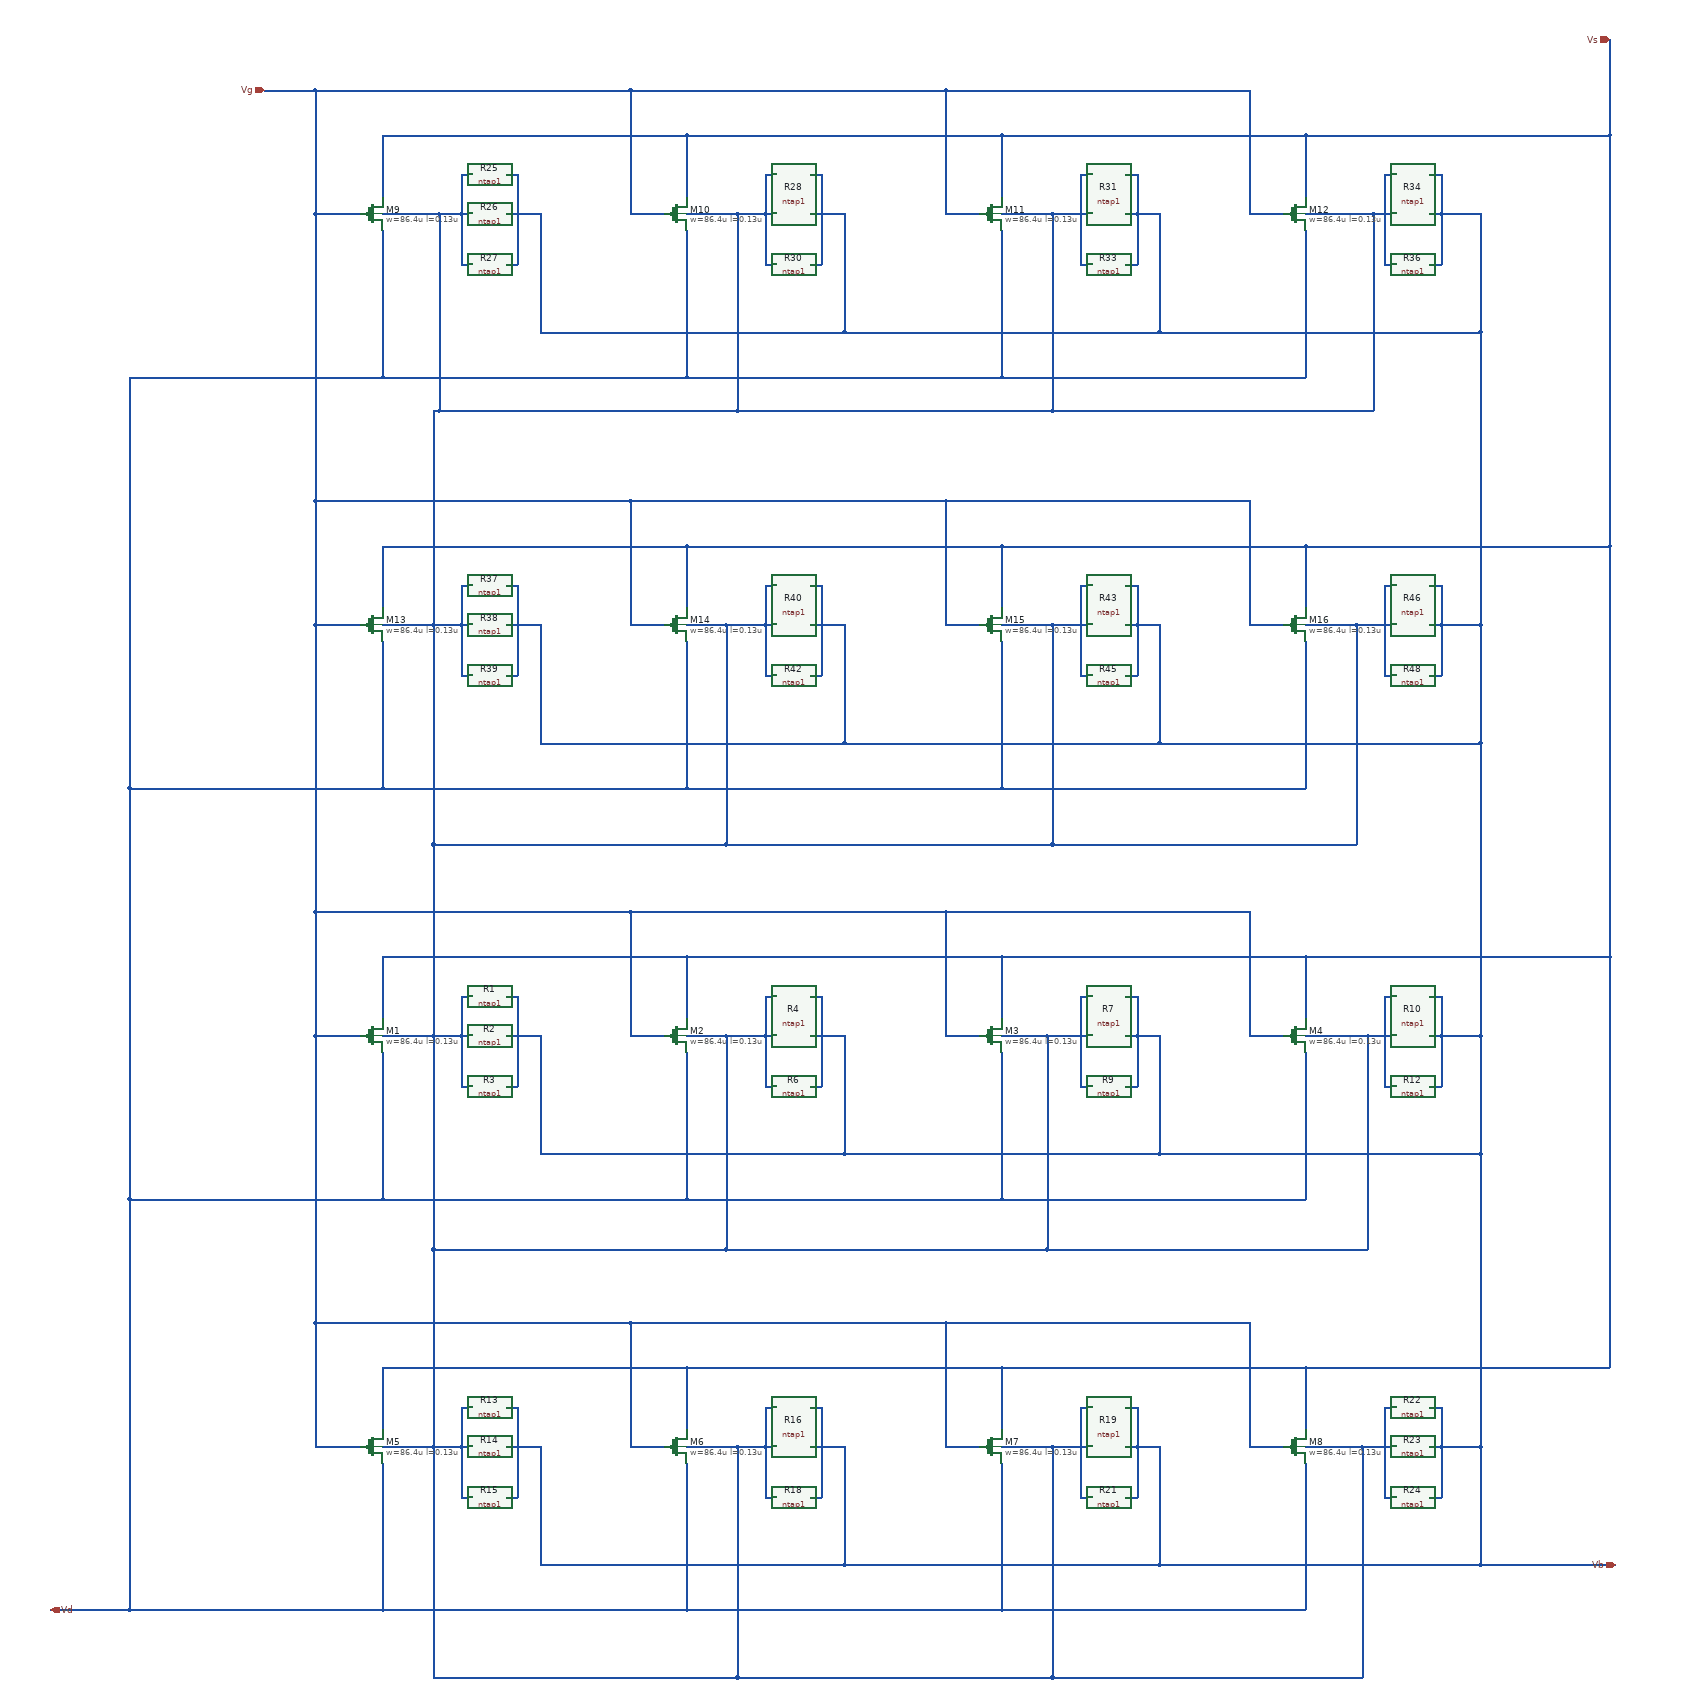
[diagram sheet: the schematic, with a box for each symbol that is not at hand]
v {xschem version=3.4.6 file_version=1.2}
G {}
K {}
V {}
S {}
E {}
N 840 -1420 890 -1420 {lab=#net1}
N 890 -1490 890 -1420 {lab=#net1}
N 890 -1490 910 -1490 {lab=#net1}
N 890 -1420 910 -1420 {lab=#net1}
N 890 -1420 890 -1330 {lab=#net1}
N 890 -1330 910 -1330 {lab=#net1}
N 970 -1490 990 -1490 {lab=Vb}
N 990 -1420 990 -1330 {lab=Vb}
N 970 -1330 990 -1330 {lab=Vb}
N 970 -1420 990 -1420 {lab=Vb}
N 990 -1490 990 -1420 {lab=Vb}
N 750 -1390 750 -1130 {lab=Vd}
N 990 -1420 1030 -1420 {lab=Vb}
N 1360 -1420 1430 -1420 {lab=#net1}
N 1430 -1490 1430 -1420 {lab=#net1}
N 1430 -1490 1450 -1490 {lab=#net1}
N 1430 -1420 1450 -1420 {lab=#net1}
N 1430 -1420 1430 -1330 {lab=#net1}
N 1430 -1330 1450 -1330 {lab=#net1}
N 1510 -1490 1530 -1490 {lab=Vb}
N 1530 -1420 1530 -1330 {lab=Vb}
N 1510 -1330 1530 -1330 {lab=Vb}
N 1510 -1420 1530 -1420 {lab=Vb}
N 1530 -1490 1530 -1420 {lab=Vb}
N 1290 -1390 1290 -1130 {lab=Vd}
N 1190 -1420 1250 -1420 {lab=Vg}
N 1530 -1420 1570 -1420 {lab=Vb}
N 1930 -1420 1990 -1420 {lab=#net1}
N 1990 -1490 1990 -1420 {lab=#net1}
N 1990 -1490 2010 -1490 {lab=#net1}
N 1990 -1420 2010 -1420 {lab=#net1}
N 1990 -1420 1990 -1330 {lab=#net1}
N 1990 -1330 2010 -1330 {lab=#net1}
N 2070 -1490 2090 -1490 {lab=Vb}
N 2090 -1420 2090 -1330 {lab=Vb}
N 2070 -1330 2090 -1330 {lab=Vb}
N 2070 -1420 2090 -1420 {lab=Vb}
N 2090 -1490 2090 -1420 {lab=Vb}
N 1850 -1390 1850 -1130 {lab=Vd}
N 1750 -1420 1810 -1420 {lab=Vg}
N 2090 -1420 2130 -1420 {lab=Vb}
N 2500 -1420 2530 -1420 {lab=#net1}
N 2530 -1490 2530 -1420 {lab=#net1}
N 2530 -1490 2550 -1490 {lab=#net1}
N 2530 -1420 2550 -1420 {lab=#net1}
N 2530 -1420 2530 -1330 {lab=#net1}
N 2530 -1330 2550 -1330 {lab=#net1}
N 2610 -1490 2630 -1490 {lab=Vb}
N 2630 -1420 2630 -1330 {lab=Vb}
N 2610 -1330 2630 -1330 {lab=Vb}
N 2610 -1420 2630 -1420 {lab=Vb}
N 2630 -1490 2630 -1420 {lab=Vb}
N 2390 -1390 2390 -1130 {lab=Vd}
N 2290 -1420 2350 -1420 {lab=Vg}
N 2630 -1420 2700 -1420 {lab=Vb}
N 750 -1560 750 -1450 {lab=Vs}
N 1850 -1560 2390 -1560 {lab=Vs}
N 2390 -1560 2390 -1450 {lab=Vs}
N 1850 -1560 1850 -1450 {lab=Vs}
N 1290 -1560 1850 -1560 {lab=Vs}
N 1290 -1560 1290 -1450 {lab=Vs}
N 750 -1560 1290 -1560 {lab=Vs}
N 1030 -1420 1030 -1210 {lab=Vb}
N 2130 -1210 2700 -1210 {lab=Vb}
N 2700 -1420 2700 -1210 {lab=Vb}
N 2130 -1420 2130 -1210 {lab=Vb}
N 1570 -1210 2130 -1210 {lab=Vb}
N 1570 -1420 1570 -1210 {lab=Vb}
N 1030 -1210 1570 -1210 {lab=Vb}
N 1850 -1130 2390 -1130 {lab=Vd}
N 1290 -1130 1850 -1130 {lab=Vd}
N 750 -1130 1290 -1130 {lab=Vd}
N 1190 -1640 1190 -1420 {lab=Vg}
N 1750 -1640 2290 -1640 {lab=Vg}
N 2290 -1640 2290 -1420 {lab=Vg}
N 1750 -1640 1750 -1420 {lab=Vg}
N 1190 -1640 1750 -1640 {lab=Vg}
N 630 -1640 1190 -1640 {lab=Vg}
N 630 -1640 630 -1420 {lab=Vg}
N 630 -1420 710 -1420 {lab=Vg}
N 840 -690 890 -690 {lab=#net1}
N 890 -760 890 -690 {lab=#net1}
N 890 -760 910 -760 {lab=#net1}
N 890 -690 910 -690 {lab=#net1}
N 890 -690 890 -600 {lab=#net1}
N 890 -600 910 -600 {lab=#net1}
N 970 -760 990 -760 {lab=Vb}
N 990 -690 990 -600 {lab=Vb}
N 970 -600 990 -600 {lab=Vb}
N 970 -690 990 -690 {lab=Vb}
N 990 -760 990 -690 {lab=Vb}
N 750 -660 750 -400 {lab=Vd}
N 990 -690 1030 -690 {lab=Vb}
N 1380 -690 1430 -690 {lab=#net1}
N 1430 -760 1430 -690 {lab=#net1}
N 1430 -760 1450 -760 {lab=#net1}
N 1430 -690 1450 -690 {lab=#net1}
N 1430 -690 1430 -600 {lab=#net1}
N 1430 -600 1450 -600 {lab=#net1}
N 1510 -760 1530 -760 {lab=Vb}
N 1530 -690 1530 -600 {lab=Vb}
N 1510 -600 1530 -600 {lab=Vb}
N 1510 -690 1530 -690 {lab=Vb}
N 1530 -760 1530 -690 {lab=Vb}
N 1290 -660 1290 -400 {lab=Vd}
N 1190 -690 1250 -690 {lab=Vg}
N 1530 -690 1570 -690 {lab=Vb}
N 1940 -690 1990 -690 {lab=#net1}
N 1990 -760 1990 -690 {lab=#net1}
N 1990 -760 2010 -760 {lab=#net1}
N 1990 -690 2010 -690 {lab=#net1}
N 1990 -690 1990 -600 {lab=#net1}
N 1990 -600 2010 -600 {lab=#net1}
N 2070 -760 2090 -760 {lab=Vb}
N 2090 -690 2090 -600 {lab=Vb}
N 2070 -600 2090 -600 {lab=Vb}
N 2070 -690 2090 -690 {lab=Vb}
N 2090 -760 2090 -690 {lab=Vb}
N 1850 -660 1850 -400 {lab=Vd}
N 1750 -690 1810 -690 {lab=Vg}
N 2090 -690 2130 -690 {lab=Vb}
N 2490 -690 2530 -690 {lab=#net1}
N 2530 -760 2530 -690 {lab=#net1}
N 2530 -760 2550 -760 {lab=#net1}
N 2530 -690 2550 -690 {lab=#net1}
N 2530 -690 2530 -600 {lab=#net1}
N 2530 -600 2550 -600 {lab=#net1}
N 2610 -760 2630 -760 {lab=Vb}
N 2630 -690 2630 -600 {lab=Vb}
N 2610 -600 2630 -600 {lab=Vb}
N 2610 -690 2630 -690 {lab=Vb}
N 2630 -760 2630 -690 {lab=Vb}
N 2390 -660 2390 -400 {lab=Vd}
N 2290 -690 2350 -690 {lab=Vg}
N 2630 -690 2700 -690 {lab=Vb}
N 750 -830 750 -720 {lab=Vs}
N 1850 -830 2390 -830 {lab=Vs}
N 2390 -830 2390 -720 {lab=Vs}
N 1850 -830 1850 -720 {lab=Vs}
N 1290 -830 1850 -830 {lab=Vs}
N 1290 -830 1290 -720 {lab=Vs}
N 750 -830 1290 -830 {lab=Vs}
N 1030 -690 1030 -480 {lab=Vb}
N 2130 -480 2700 -480 {lab=Vb}
N 2700 -690 2700 -480 {lab=Vb}
N 2130 -690 2130 -480 {lab=Vb}
N 1570 -480 2130 -480 {lab=Vb}
N 1570 -690 1570 -480 {lab=Vb}
N 1030 -480 1570 -480 {lab=Vb}
N 1850 -400 2390 -400 {lab=Vd}
N 1290 -400 1850 -400 {lab=Vd}
N 750 -400 1290 -400 {lab=Vd}
N 1190 -910 1190 -690 {lab=Vg}
N 1750 -910 2290 -910 {lab=Vg}
N 2290 -910 2290 -690 {lab=Vg}
N 1750 -910 1750 -690 {lab=Vg}
N 1190 -910 1750 -910 {lab=Vg}
N 630 -910 1190 -910 {lab=Vg}
N 630 -910 630 -690 {lab=Vg}
N 630 -690 710 -690 {lab=Vg}
N 850 -2880 890 -2880 {lab=#net1}
N 890 -2950 890 -2880 {lab=#net1}
N 890 -2950 910 -2950 {lab=#net1}
N 890 -2880 910 -2880 {lab=#net1}
N 890 -2880 890 -2790 {lab=#net1}
N 890 -2790 910 -2790 {lab=#net1}
N 970 -2950 990 -2950 {lab=Vb}
N 990 -2880 990 -2790 {lab=Vb}
N 970 -2790 990 -2790 {lab=Vb}
N 970 -2880 990 -2880 {lab=Vb}
N 990 -2950 990 -2880 {lab=Vb}
N 750 -2850 750 -2590 {lab=Vd}
N 990 -2880 1030 -2880 {lab=Vb}
N 1380 -2880 1430 -2880 {lab=#net1}
N 1430 -2950 1430 -2880 {lab=#net1}
N 1430 -2950 1450 -2950 {lab=#net1}
N 1430 -2880 1450 -2880 {lab=#net1}
N 1430 -2880 1430 -2790 {lab=#net1}
N 1430 -2790 1450 -2790 {lab=#net1}
N 1510 -2950 1530 -2950 {lab=Vb}
N 1530 -2880 1530 -2790 {lab=Vb}
N 1510 -2790 1530 -2790 {lab=Vb}
N 1510 -2880 1530 -2880 {lab=Vb}
N 1530 -2950 1530 -2880 {lab=Vb}
N 1290 -2850 1290 -2590 {lab=Vd}
N 1190 -2880 1250 -2880 {lab=Vg}
N 1530 -2880 1570 -2880 {lab=Vb}
N 1940 -2880 1990 -2880 {lab=#net1}
N 1990 -2950 1990 -2880 {lab=#net1}
N 1990 -2950 2010 -2950 {lab=#net1}
N 1990 -2880 2010 -2880 {lab=#net1}
N 1990 -2880 1990 -2790 {lab=#net1}
N 1990 -2790 2010 -2790 {lab=#net1}
N 2070 -2950 2090 -2950 {lab=Vb}
N 2090 -2880 2090 -2790 {lab=Vb}
N 2070 -2790 2090 -2790 {lab=Vb}
N 2070 -2880 2090 -2880 {lab=Vb}
N 2090 -2950 2090 -2880 {lab=Vb}
N 1850 -2850 1850 -2590 {lab=Vd}
N 1750 -2880 1810 -2880 {lab=Vg}
N 2090 -2880 2130 -2880 {lab=Vb}
N 2510 -2880 2530 -2880 {lab=#net1}
N 2530 -2950 2530 -2880 {lab=#net1}
N 2530 -2950 2550 -2950 {lab=#net1}
N 2530 -2880 2550 -2880 {lab=#net1}
N 2530 -2880 2530 -2790 {lab=#net1}
N 2530 -2790 2550 -2790 {lab=#net1}
N 2610 -2950 2630 -2950 {lab=Vb}
N 2630 -2880 2630 -2790 {lab=Vb}
N 2610 -2790 2630 -2790 {lab=Vb}
N 2610 -2880 2630 -2880 {lab=Vb}
N 2630 -2950 2630 -2880 {lab=Vb}
N 2390 -2850 2390 -2590 {lab=Vd}
N 2290 -2880 2350 -2880 {lab=Vg}
N 2630 -2880 2700 -2880 {lab=Vb}
N 750 -3020 750 -2910 {lab=Vs}
N 1850 -3020 2390 -3020 {lab=Vs}
N 2390 -3020 2390 -2910 {lab=Vs}
N 1850 -3020 1850 -2910 {lab=Vs}
N 1290 -3020 1850 -3020 {lab=Vs}
N 1290 -3020 1290 -2910 {lab=Vs}
N 750 -3020 1290 -3020 {lab=Vs}
N 1030 -2880 1030 -2670 {lab=Vb}
N 2130 -2670 2700 -2670 {lab=Vb}
N 2700 -2880 2700 -2670 {lab=Vb}
N 2130 -2880 2130 -2670 {lab=Vb}
N 1570 -2670 2130 -2670 {lab=Vb}
N 1570 -2880 1570 -2670 {lab=Vb}
N 1030 -2670 1570 -2670 {lab=Vb}
N 1850 -2590 2390 -2590 {lab=Vd}
N 1290 -2590 1850 -2590 {lab=Vd}
N 750 -2590 1290 -2590 {lab=Vd}
N 1190 -3100 1190 -2880 {lab=Vg}
N 1750 -3100 2290 -3100 {lab=Vg}
N 2290 -3100 2290 -2880 {lab=Vg}
N 1750 -3100 1750 -2880 {lab=Vg}
N 1190 -3100 1750 -3100 {lab=Vg}
N 630 -3100 1190 -3100 {lab=Vg}
N 630 -3100 630 -2880 {lab=Vg}
N 630 -2880 710 -2880 {lab=Vg}
N 840 -2150 890 -2150 {lab=#net1}
N 890 -2220 890 -2150 {lab=#net1}
N 890 -2220 910 -2220 {lab=#net1}
N 890 -2150 910 -2150 {lab=#net1}
N 890 -2150 890 -2060 {lab=#net1}
N 890 -2060 910 -2060 {lab=#net1}
N 970 -2220 990 -2220 {lab=Vb}
N 990 -2150 990 -2060 {lab=Vb}
N 970 -2060 990 -2060 {lab=Vb}
N 970 -2150 990 -2150 {lab=Vb}
N 990 -2220 990 -2150 {lab=Vb}
N 750 -2120 750 -1860 {lab=Vd}
N 990 -2150 1030 -2150 {lab=Vb}
N 1360 -2150 1430 -2150 {lab=#net1}
N 1430 -2220 1430 -2150 {lab=#net1}
N 1430 -2220 1450 -2220 {lab=#net1}
N 1430 -2150 1450 -2150 {lab=#net1}
N 1430 -2150 1430 -2060 {lab=#net1}
N 1430 -2060 1450 -2060 {lab=#net1}
N 1510 -2220 1530 -2220 {lab=Vb}
N 1530 -2150 1530 -2060 {lab=Vb}
N 1510 -2060 1530 -2060 {lab=Vb}
N 1510 -2150 1530 -2150 {lab=Vb}
N 1530 -2220 1530 -2150 {lab=Vb}
N 1290 -2120 1290 -1860 {lab=Vd}
N 1190 -2150 1250 -2150 {lab=Vg}
N 1530 -2150 1570 -2150 {lab=Vb}
N 1990 -2220 1990 -2150 {lab=#net1}
N 1990 -2220 2010 -2220 {lab=#net1}
N 1990 -2150 2010 -2150 {lab=#net1}
N 1990 -2150 1990 -2060 {lab=#net1}
N 1990 -2060 2010 -2060 {lab=#net1}
N 2070 -2220 2090 -2220 {lab=Vb}
N 2090 -2150 2090 -2060 {lab=Vb}
N 2070 -2060 2090 -2060 {lab=Vb}
N 2070 -2150 2090 -2150 {lab=Vb}
N 2090 -2220 2090 -2150 {lab=Vb}
N 1850 -2120 1850 -1860 {lab=Vd}
N 1750 -2150 1810 -2150 {lab=Vg}
N 2090 -2150 2130 -2150 {lab=Vb}
N 2480 -2150 2530 -2150 {lab=#net1}
N 2530 -2220 2530 -2150 {lab=#net1}
N 2530 -2220 2550 -2220 {lab=#net1}
N 2530 -2150 2550 -2150 {lab=#net1}
N 2530 -2150 2530 -2060 {lab=#net1}
N 2530 -2060 2550 -2060 {lab=#net1}
N 2610 -2220 2630 -2220 {lab=Vb}
N 2630 -2150 2630 -2060 {lab=Vb}
N 2610 -2060 2630 -2060 {lab=Vb}
N 2610 -2150 2630 -2150 {lab=Vb}
N 2630 -2220 2630 -2150 {lab=Vb}
N 2390 -2120 2390 -1860 {lab=Vd}
N 2290 -2150 2350 -2150 {lab=Vg}
N 2630 -2150 2700 -2150 {lab=Vb}
N 750 -2290 750 -2180 {lab=Vs}
N 1850 -2290 2390 -2290 {lab=Vs}
N 2390 -2290 2390 -2180 {lab=Vs}
N 1850 -2290 1850 -2180 {lab=Vs}
N 1290 -2290 1850 -2290 {lab=Vs}
N 1290 -2290 1290 -2180 {lab=Vs}
N 750 -2290 1290 -2290 {lab=Vs}
N 1030 -2150 1030 -1940 {lab=Vb}
N 2130 -1940 2700 -1940 {lab=Vb}
N 2130 -2150 2130 -1940 {lab=Vb}
N 1570 -1940 2130 -1940 {lab=Vb}
N 1570 -2150 1570 -1940 {lab=Vb}
N 1030 -1940 1570 -1940 {lab=Vb}
N 1850 -1860 2390 -1860 {lab=Vd}
N 1290 -1860 1850 -1860 {lab=Vd}
N 750 -1860 1290 -1860 {lab=Vd}
N 1190 -2370 1190 -2150 {lab=Vg}
N 1750 -2370 2290 -2370 {lab=Vg}
N 2290 -2370 2290 -2150 {lab=Vg}
N 1750 -2370 1750 -2150 {lab=Vg}
N 1190 -2370 1750 -2370 {lab=Vg}
N 630 -2370 1190 -2370 {lab=Vg}
N 630 -2150 710 -2150 {lab=Vg}
N 2390 -3020 2930 -3020 {lab=Vs}
N 2930 -3190 2930 -3020 {lab=Vs}
N 2390 -2290 2930 -2290 {lab=Vs}
N 2930 -3020 2930 -2290 {lab=Vs}
N 2390 -1560 2930 -1560 {lab=Vs}
N 2930 -2290 2930 -1560 {lab=Vs}
N 2390 -830 2930 -830 {lab=Vs}
N 2930 -1560 2930 -830 {lab=Vs}
N 2700 -2150 2700 -1940 {lab=Vb}
N 2700 -1940 2700 -1420 {lab=Vb}
N 2700 -1210 2700 -690 {lab=Vb}
N 2700 -480 2940 -480 {lab=Vb}
N 630 -2370 630 -2150 {lab=Vg}
N 630 -2880 630 -2370 {lab=Vg}
N 630 -2150 630 -1640 {lab=Vg}
N 630 -1420 630 -910 {lab=Vg}
N 540 -3100 630 -3100 {lab=Vg}
N 300 -2590 750 -2590 {lab=Vd}
N 300 -1130 300 -400 {lab=Vd}
N 300 -400 750 -400 {lab=Vd}
N 160 -400 300 -400 {lab=Vd}
N 300 -1130 750 -1130 {lab=Vd}
N 300 -1860 300 -1130 {lab=Vd}
N 300 -1860 750 -1860 {lab=Vd}
N 300 -2590 300 -1860 {lab=Vd}
N 2700 -2670 2700 -2150 {lab=Vb}
N 850 -2880 850 -2530 {lab=#net1}
N 750 -2880 850 -2880 {lab=#net1}
N 1940 -2530 2510 -2530 {lab=#net1}
N 2510 -2880 2510 -2530 {lab=#net1}
N 2390 -2880 2510 -2880 {lab=#net1}
N 1940 -2880 1940 -2530 {lab=#net1}
N 1850 -2880 1940 -2880 {lab=#net1}
N 1380 -2530 1940 -2530 {lab=#net1}
N 1380 -2880 1380 -2530 {lab=#net1}
N 1290 -2880 1380 -2880 {lab=#net1}
N 850 -2530 1380 -2530 {lab=#net1}
N 750 -2150 840 -2150 {lab=#net1}
N 1940 -1760 2480 -1760 {lab=#net1}
N 2480 -2150 2480 -1760 {lab=#net1}
N 2390 -2150 2480 -2150 {lab=#net1}
N 1940 -2150 1990 -2150 {lab=#net1}
N 1940 -2150 1940 -1760 {lab=#net1}
N 1850 -2150 1940 -2150 {lab=#net1}
N 1360 -1760 1940 -1760 {lab=#net1}
N 1360 -2150 1360 -1760 {lab=#net1}
N 1290 -2150 1360 -2150 {lab=#net1}
N 840 -1760 1360 -1760 {lab=#net1}
N 840 -1420 840 -1040 {lab=#net1}
N 750 -1420 840 -1420 {lab=#net1}
N 1930 -1040 2500 -1040 {lab=#net1}
N 2500 -1420 2500 -1040 {lab=#net1}
N 2390 -1420 2500 -1420 {lab=#net1}
N 1930 -1420 1930 -1040 {lab=#net1}
N 1850 -1420 1930 -1420 {lab=#net1}
N 1360 -1040 1930 -1040 {lab=#net1}
N 1360 -1420 1360 -1040 {lab=#net1}
N 1290 -1420 1360 -1420 {lab=#net1}
N 840 -1040 1360 -1040 {lab=#net1}
N 840 -690 840 -280 {lab=#net1}
N 750 -690 840 -690 {lab=#net1}
N 1940 -280 2490 -280 {lab=#net1}
N 2490 -690 2490 -280 {lab=#net1}
N 2390 -690 2490 -690 {lab=#net1}
N 1940 -690 1940 -280 {lab=#net1}
N 1850 -690 1940 -690 {lab=#net1}
N 1380 -280 1940 -280 {lab=#net1}
N 1380 -690 1380 -280 {lab=#net1}
N 1290 -690 1380 -690 {lab=#net1}
N 840 -280 1380 -280 {lab=#net1}
N 840 -2150 840 -1760 {lab=#net1}
N 840 -2530 840 -2150 {lab=#net1}
N 840 -2530 850 -2530 {lab=#net1}
N 840 -1760 840 -1420 {lab=#net1}
N 840 -1040 840 -690 {lab=#net1}
C {ipin.sym} 540 -3100 0 0 {name=p1 lab=Vg}
C {iopin.sym} 2930 -3190 0 0 {name=p2 lab=Vs}
C {iopin.sym} 160 -400 0 1 {name=p3 lab=Vd}
C {iopin.sym} 2940 -480 0 0 {name=p4 lab=Vb}
C {sg13g2_pr/sg13_lv_pmos.sym} 730 -1420 0 0 {name=M1
l=0.13u
w=86.4u
ng=36
m=1
model=sg13_lv_pmos
spiceprefix=X
}
C {sg13g2_pr/ntap1.sym} 940 -1490 1 0 {name=R1
model=ntap1
spiceprefix=X
w=62e-6
l=1e-6
}
C {sg13g2_pr/ntap1.sym} 940 -1420 1 0 {name=R2
model=ntap1
spiceprefix=X
w=62e-6
l=1e-6
}
C {sg13g2_pr/ntap1.sym} 940 -1330 1 0 {name=R3
model=ntap1
spiceprefix=X
w=62e-6
l=1e-6
}
C {sg13g2_pr/sg13_lv_pmos.sym} 1270 -1420 0 0 {name=M2
l=0.13u
w=86.4u
ng=36
m=1
model=sg13_lv_pmos
spiceprefix=X
}
C {sg13g2_pr/ntap1.sym} 1480 -1490 1 0 {name=R4
model=ntap1
spiceprefix=X
w=62e-6
l=1e-6
}
C {sg13g2_pr/ntap1.sym} 1480 -1330 1 0 {name=R6
model=ntap1
spiceprefix=X
w=62e-6
l=1e-6
}
C {sg13g2_pr/sg13_lv_pmos.sym} 1830 -1420 0 0 {name=M3
l=0.13u
w=86.4u
ng=36
m=1
model=sg13_lv_pmos
spiceprefix=X
}
C {sg13g2_pr/ntap1.sym} 2040 -1490 1 0 {name=R7
model=ntap1
spiceprefix=X
w=62e-6
l=1e-6
}
C {sg13g2_pr/ntap1.sym} 2040 -1330 1 0 {name=R9
model=ntap1
spiceprefix=X
w=62e-6
l=1e-6
}
C {sg13g2_pr/sg13_lv_pmos.sym} 2370 -1420 0 0 {name=M4
l=0.13u
w=86.4u
ng=36
m=1
model=sg13_lv_pmos
spiceprefix=X
}
C {sg13g2_pr/ntap1.sym} 2580 -1490 1 0 {name=R10
model=ntap1
spiceprefix=X
w=62e-6
l=1e-6
}
C {sg13g2_pr/ntap1.sym} 2580 -1330 1 0 {name=R12
model=ntap1
spiceprefix=X
w=62e-6
l=1e-6
}
C {sg13g2_pr/sg13_lv_pmos.sym} 730 -690 0 0 {name=M5
l=0.13u
w=86.4u
ng=36
m=1
model=sg13_lv_pmos
spiceprefix=X
}
C {sg13g2_pr/ntap1.sym} 940 -760 1 0 {name=R13
model=ntap1
spiceprefix=X
w=62e-6
l=1e-6
}
C {sg13g2_pr/ntap1.sym} 940 -690 1 0 {name=R14
model=ntap1
spiceprefix=X
w=62e-6
l=1e-6
}
C {sg13g2_pr/ntap1.sym} 940 -600 1 0 {name=R15
model=ntap1
spiceprefix=X
w=62e-6
l=1e-6
}
C {sg13g2_pr/sg13_lv_pmos.sym} 1270 -690 0 0 {name=M6
l=0.13u
w=86.4u
ng=36
m=1
model=sg13_lv_pmos
spiceprefix=X
}
C {sg13g2_pr/ntap1.sym} 1480 -760 1 0 {name=R16
model=ntap1
spiceprefix=X
w=62e-6
l=1e-6
}
C {sg13g2_pr/ntap1.sym} 1480 -600 1 0 {name=R18
model=ntap1
spiceprefix=X
w=62e-6
l=1e-6
}
C {sg13g2_pr/sg13_lv_pmos.sym} 1830 -690 0 0 {name=M7
l=0.13u
w=86.4u
ng=36
m=1
model=sg13_lv_pmos
spiceprefix=X
}
C {sg13g2_pr/ntap1.sym} 2040 -760 1 0 {name=R19
model=ntap1
spiceprefix=X
w=62e-6
l=1e-6
}
C {sg13g2_pr/ntap1.sym} 2040 -600 1 0 {name=R21
model=ntap1
spiceprefix=X
w=62e-6
l=1e-6
}
C {sg13g2_pr/sg13_lv_pmos.sym} 2370 -690 0 0 {name=M8
l=0.13u
w=86.4u
ng=36
m=1
model=sg13_lv_pmos
spiceprefix=X
}
C {sg13g2_pr/ntap1.sym} 2580 -760 1 0 {name=R22
model=ntap1
spiceprefix=X
w=62e-6
l=1e-6
}
C {sg13g2_pr/ntap1.sym} 2580 -690 1 0 {name=R23
model=ntap1
spiceprefix=X
w=62e-6
l=1e-6
}
C {sg13g2_pr/ntap1.sym} 2580 -600 1 0 {name=R24
model=ntap1
spiceprefix=X
w=62e-6
l=1e-6
}
C {sg13g2_pr/sg13_lv_pmos.sym} 730 -2880 0 0 {name=M9
l=0.13u
w=86.4u
ng=36
m=1
model=sg13_lv_pmos
spiceprefix=X
}
C {sg13g2_pr/ntap1.sym} 940 -2950 1 0 {name=R25
model=ntap1
spiceprefix=X
w=62e-6
l=1e-6
}
C {sg13g2_pr/ntap1.sym} 940 -2880 1 0 {name=R26
model=ntap1
spiceprefix=X
w=62e-6
l=1e-6
}
C {sg13g2_pr/ntap1.sym} 940 -2790 1 0 {name=R27
model=ntap1
spiceprefix=X
w=62e-6
l=1e-6
}
C {sg13g2_pr/sg13_lv_pmos.sym} 1270 -2880 0 0 {name=M10
l=0.13u
w=86.4u
ng=36
m=1
model=sg13_lv_pmos
spiceprefix=X
}
C {sg13g2_pr/ntap1.sym} 1480 -2950 1 0 {name=R28
model=ntap1
spiceprefix=X
w=62e-6
l=1e-6
}
C {sg13g2_pr/ntap1.sym} 1480 -2790 1 0 {name=R30
model=ntap1
spiceprefix=X
w=62e-6
l=1e-6
}
C {sg13g2_pr/sg13_lv_pmos.sym} 1830 -2880 0 0 {name=M11
l=0.13u
w=86.4u
ng=36
m=1
model=sg13_lv_pmos
spiceprefix=X
}
C {sg13g2_pr/ntap1.sym} 2040 -2950 1 0 {name=R31
model=ntap1
spiceprefix=X
w=62e-6
l=1e-6
}
C {sg13g2_pr/ntap1.sym} 2040 -2790 1 0 {name=R33
model=ntap1
spiceprefix=X
w=62e-6
l=1e-6
}
C {sg13g2_pr/sg13_lv_pmos.sym} 2370 -2880 0 0 {name=M12
l=0.13u
w=86.4u
ng=36
m=1
model=sg13_lv_pmos
spiceprefix=X
}
C {sg13g2_pr/ntap1.sym} 2580 -2950 1 0 {name=R34
model=ntap1
spiceprefix=X
w=62e-6
l=1e-6
}
C {sg13g2_pr/ntap1.sym} 2580 -2790 1 0 {name=R36
model=ntap1
spiceprefix=X
w=62e-6
l=1e-6
}
C {sg13g2_pr/sg13_lv_pmos.sym} 730 -2150 0 0 {name=M13
l=0.13u
w=86.4u
ng=36
m=1
model=sg13_lv_pmos
spiceprefix=X
}
C {sg13g2_pr/ntap1.sym} 940 -2220 1 0 {name=R37
model=ntap1
spiceprefix=X
w=62e-6
l=1e-6
}
C {sg13g2_pr/ntap1.sym} 940 -2150 1 0 {name=R38
model=ntap1
spiceprefix=X
w=62e-6
l=1e-6
}
C {sg13g2_pr/ntap1.sym} 940 -2060 1 0 {name=R39
model=ntap1
spiceprefix=X
w=62e-6
l=1e-6
}
C {sg13g2_pr/sg13_lv_pmos.sym} 1270 -2150 0 0 {name=M14
l=0.13u
w=86.4u
ng=36
m=1
model=sg13_lv_pmos
spiceprefix=X
}
C {sg13g2_pr/ntap1.sym} 1480 -2220 1 0 {name=R40
model=ntap1
spiceprefix=X
w=62e-6
l=1e-6
}
C {sg13g2_pr/ntap1.sym} 1480 -2060 1 0 {name=R42
model=ntap1
spiceprefix=X
w=62e-6
l=1e-6
}
C {sg13g2_pr/sg13_lv_pmos.sym} 1830 -2150 0 0 {name=M15
l=0.13u
w=86.4u
ng=36
m=1
model=sg13_lv_pmos
spiceprefix=X
}
C {sg13g2_pr/ntap1.sym} 2040 -2220 1 0 {name=R43
model=ntap1
spiceprefix=X
w=62e-6
l=1e-6
}
C {sg13g2_pr/ntap1.sym} 2040 -2060 1 0 {name=R45
model=ntap1
spiceprefix=X
w=62e-6
l=1e-6
}
C {sg13g2_pr/sg13_lv_pmos.sym} 2370 -2150 0 0 {name=M16
l=0.13u
w=86.4u
ng=36
m=1
model=sg13_lv_pmos
spiceprefix=X
}
C {sg13g2_pr/ntap1.sym} 2580 -2220 1 0 {name=R46
model=ntap1
spiceprefix=X
w=62e-6
l=1e-6
}
C {sg13g2_pr/ntap1.sym} 2580 -2060 1 0 {name=R48
model=ntap1
spiceprefix=X
w=62e-6
l=1e-6
}
